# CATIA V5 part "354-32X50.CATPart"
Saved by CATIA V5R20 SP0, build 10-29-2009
Part number: 354-32X50
Definition: NONE
Nomenclature: 354-32X50
Source: Unknown
Description: 354-32X50
Bounding box of the stored display mesh (mm): x -25 to 25, y -22.5 to 22.5, z -22.5 to 22.5
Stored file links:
  C:\Users\Utente\Desktop\IO LAVORO\3D X SITO CF\X SITO\PLASTICA\354\354-32X50.CATPart

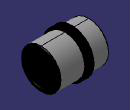
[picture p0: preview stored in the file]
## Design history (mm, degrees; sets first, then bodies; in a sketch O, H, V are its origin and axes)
Body1 "354-32X50" (main body)
  Solid1: solid without history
